VERSION 5.7 ;
  NOWIREEXTENSIONATPIN ON ;
  DIVIDERCHAR "/" ;
  BUSBITCHARS "[]" ;
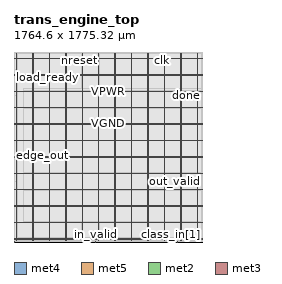
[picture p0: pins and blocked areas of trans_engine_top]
MACRO trans_engine_top
  CLASS BLOCK ;
  FOREIGN trans_engine_top ;
  ORIGIN 0.000 0.000 ;
  SIZE 1764.600 BY 1775.320 ;
  PIN VGND
    DIRECTION INOUT ;
    USE GROUND ;
    PORT
      LAYER met4 ;
        RECT 24.340 10.640 25.940 1762.800 ;
    END
    PORT
      LAYER met4 ;
        RECT 177.940 10.640 179.540 1762.800 ;
    END
    PORT
      LAYER met4 ;
        RECT 331.540 10.640 333.140 1762.800 ;
    END
    PORT
      LAYER met4 ;
        RECT 485.140 10.640 486.740 1762.800 ;
    END
    PORT
      LAYER met4 ;
        RECT 638.740 10.640 640.340 1762.800 ;
    END
    PORT
      LAYER met4 ;
        RECT 792.340 10.640 793.940 1762.800 ;
    END
    PORT
      LAYER met4 ;
        RECT 945.940 10.640 947.540 1762.800 ;
    END
    PORT
      LAYER met4 ;
        RECT 1099.540 10.640 1101.140 1762.800 ;
    END
    PORT
      LAYER met4 ;
        RECT 1253.140 10.640 1254.740 1762.800 ;
    END
    PORT
      LAYER met4 ;
        RECT 1406.740 10.640 1408.340 1762.800 ;
    END
    PORT
      LAYER met4 ;
        RECT 1560.340 10.640 1561.940 1762.800 ;
    END
    PORT
      LAYER met4 ;
        RECT 1713.940 10.640 1715.540 1762.800 ;
    END
    PORT
      LAYER met5 ;
        RECT 5.280 30.030 1759.280 31.630 ;
    END
    PORT
      LAYER met5 ;
        RECT 5.280 183.210 1759.280 184.810 ;
    END
    PORT
      LAYER met5 ;
        RECT 5.280 336.390 1759.280 337.990 ;
    END
    PORT
      LAYER met5 ;
        RECT 5.280 489.570 1759.280 491.170 ;
    END
    PORT
      LAYER met5 ;
        RECT 5.280 642.750 1759.280 644.350 ;
    END
    PORT
      LAYER met5 ;
        RECT 5.280 795.930 1759.280 797.530 ;
    END
    PORT
      LAYER met5 ;
        RECT 5.280 949.110 1759.280 950.710 ;
    END
    PORT
      LAYER met5 ;
        RECT 5.280 1102.290 1759.280 1103.890 ;
    END
    PORT
      LAYER met5 ;
        RECT 5.280 1255.470 1759.280 1257.070 ;
    END
    PORT
      LAYER met5 ;
        RECT 5.280 1408.650 1759.280 1410.250 ;
    END
    PORT
      LAYER met5 ;
        RECT 5.280 1561.830 1759.280 1563.430 ;
    END
    PORT
      LAYER met5 ;
        RECT 5.280 1715.010 1759.280 1716.610 ;
    END
  END VGND
  PIN VPWR
    DIRECTION INOUT ;
    USE POWER ;
    PORT
      LAYER met4 ;
        RECT 21.040 10.640 22.640 1762.800 ;
    END
    PORT
      LAYER met4 ;
        RECT 174.640 10.640 176.240 1762.800 ;
    END
    PORT
      LAYER met4 ;
        RECT 328.240 10.640 329.840 1762.800 ;
    END
    PORT
      LAYER met4 ;
        RECT 481.840 10.640 483.440 1762.800 ;
    END
    PORT
      LAYER met4 ;
        RECT 635.440 10.640 637.040 1762.800 ;
    END
    PORT
      LAYER met4 ;
        RECT 789.040 10.640 790.640 1762.800 ;
    END
    PORT
      LAYER met4 ;
        RECT 942.640 10.640 944.240 1762.800 ;
    END
    PORT
      LAYER met4 ;
        RECT 1096.240 10.640 1097.840 1762.800 ;
    END
    PORT
      LAYER met4 ;
        RECT 1249.840 10.640 1251.440 1762.800 ;
    END
    PORT
      LAYER met4 ;
        RECT 1403.440 10.640 1405.040 1762.800 ;
    END
    PORT
      LAYER met4 ;
        RECT 1557.040 10.640 1558.640 1762.800 ;
    END
    PORT
      LAYER met4 ;
        RECT 1710.640 10.640 1712.240 1762.800 ;
    END
    PORT
      LAYER met5 ;
        RECT 5.280 26.730 1759.280 28.330 ;
    END
    PORT
      LAYER met5 ;
        RECT 5.280 179.910 1759.280 181.510 ;
    END
    PORT
      LAYER met5 ;
        RECT 5.280 333.090 1759.280 334.690 ;
    END
    PORT
      LAYER met5 ;
        RECT 5.280 486.270 1759.280 487.870 ;
    END
    PORT
      LAYER met5 ;
        RECT 5.280 639.450 1759.280 641.050 ;
    END
    PORT
      LAYER met5 ;
        RECT 5.280 792.630 1759.280 794.230 ;
    END
    PORT
      LAYER met5 ;
        RECT 5.280 945.810 1759.280 947.410 ;
    END
    PORT
      LAYER met5 ;
        RECT 5.280 1098.990 1759.280 1100.590 ;
    END
    PORT
      LAYER met5 ;
        RECT 5.280 1252.170 1759.280 1253.770 ;
    END
    PORT
      LAYER met5 ;
        RECT 5.280 1405.350 1759.280 1406.950 ;
    END
    PORT
      LAYER met5 ;
        RECT 5.280 1558.530 1759.280 1560.130 ;
    END
    PORT
      LAYER met5 ;
        RECT 5.280 1711.710 1759.280 1713.310 ;
    END
  END VPWR
  PIN class_in[0]
    DIRECTION INPUT ;
    USE SIGNAL ;
    ANTENNAGATEAREA 0.426000 ;
    PORT
      LAYER met2 ;
        RECT 0.090 0.000 0.370 4.000 ;
    END
  END class_in[0]
  PIN class_in[1]
    DIRECTION INPUT ;
    USE SIGNAL ;
    ANTENNAGATEAREA 0.852000 ;
    PORT
      LAYER met2 ;
        RECT 1529.590 0.000 1529.870 4.000 ;
    END
  END class_in[1]
  PIN clk
    DIRECTION INPUT ;
    USE SIGNAL ;
    ANTENNAGATEAREA 0.852000 ;
    PORT
      LAYER met2 ;
        RECT 1381.470 1771.320 1381.750 1775.320 ;
    END
  END clk
  PIN done
    DIRECTION OUTPUT TRISTATE ;
    USE SIGNAL ;
    ANTENNADIFFAREA 0.445500 ;
    PORT
      LAYER met3 ;
        RECT 1760.600 1370.240 1764.600 1370.840 ;
    END
  END done
  PIN edge_out
    DIRECTION OUTPUT TRISTATE ;
    USE SIGNAL ;
    ANTENNADIFFAREA 0.795200 ;
    PORT
      LAYER met3 ;
        RECT 0.000 805.840 4.000 806.440 ;
    END
  END edge_out
  PIN in_valid
    DIRECTION INPUT ;
    USE SIGNAL ;
    ANTENNAGATEAREA 0.213000 ;
    PORT
      LAYER met2 ;
        RECT 763.230 0.000 763.510 4.000 ;
    END
  END in_valid
  PIN load_ready
    DIRECTION OUTPUT TRISTATE ;
    USE SIGNAL ;
    ANTENNADIFFAREA 0.795200 ;
    PORT
      LAYER met3 ;
        RECT 0.000 1615.040 4.000 1615.640 ;
    END
  END load_ready
  PIN nreset
    DIRECTION INPUT ;
    USE SIGNAL ;
    ANTENNAGATEAREA 0.126000 ;
    PORT
      LAYER met2 ;
        RECT 615.110 1771.320 615.390 1775.320 ;
    END
  END nreset
  PIN out_valid
    DIRECTION OUTPUT TRISTATE ;
    USE SIGNAL ;
    ANTENNADIFFAREA 0.445500 ;
    PORT
      LAYER met3 ;
        RECT 1760.600 561.040 1764.600 561.640 ;
    END
  END out_valid
  OBS
      LAYER li1 ;
        RECT 5.520 10.795 1759.040 1762.645 ;
      LAYER met1 ;
        RECT 0.070 10.640 1764.490 1762.800 ;
      LAYER met2 ;
        RECT 0.100 1771.040 614.830 1771.810 ;
        RECT 615.670 1771.040 1381.190 1771.810 ;
        RECT 1382.030 1771.040 1764.460 1771.810 ;
        RECT 0.100 4.280 1764.460 1771.040 ;
        RECT 0.650 3.670 762.950 4.280 ;
        RECT 763.790 3.670 1529.310 4.280 ;
        RECT 1530.150 3.670 1764.460 4.280 ;
      LAYER met3 ;
        RECT 4.000 1616.040 1763.115 1762.725 ;
        RECT 4.400 1614.640 1763.115 1616.040 ;
        RECT 4.000 1371.240 1763.115 1614.640 ;
        RECT 4.000 1369.840 1760.200 1371.240 ;
        RECT 4.000 806.840 1763.115 1369.840 ;
        RECT 4.400 805.440 1763.115 806.840 ;
        RECT 4.000 562.040 1763.115 805.440 ;
        RECT 4.000 560.640 1760.200 562.040 ;
        RECT 4.000 10.715 1763.115 560.640 ;
      LAYER met4 ;
        RECT 30.655 40.975 174.240 1761.025 ;
        RECT 176.640 40.975 177.540 1761.025 ;
        RECT 179.940 40.975 327.840 1761.025 ;
        RECT 330.240 40.975 331.140 1761.025 ;
        RECT 333.540 40.975 481.440 1761.025 ;
        RECT 483.840 40.975 484.740 1761.025 ;
        RECT 487.140 40.975 635.040 1761.025 ;
        RECT 637.440 40.975 638.340 1761.025 ;
        RECT 640.740 40.975 788.640 1761.025 ;
        RECT 791.040 40.975 791.940 1761.025 ;
        RECT 794.340 40.975 942.240 1761.025 ;
        RECT 944.640 40.975 945.540 1761.025 ;
        RECT 947.940 40.975 1095.840 1761.025 ;
        RECT 1098.240 40.975 1099.140 1761.025 ;
        RECT 1101.540 40.975 1249.440 1761.025 ;
        RECT 1251.840 40.975 1252.740 1761.025 ;
        RECT 1255.140 40.975 1403.040 1761.025 ;
        RECT 1405.440 40.975 1406.340 1761.025 ;
        RECT 1408.740 40.975 1556.640 1761.025 ;
        RECT 1559.040 40.975 1559.940 1761.025 ;
        RECT 1562.340 40.975 1710.240 1761.025 ;
        RECT 1712.640 40.975 1713.540 1761.025 ;
        RECT 1715.940 40.975 1752.730 1761.025 ;
      LAYER met5 ;
        RECT 87.980 1411.850 1752.940 1430.500 ;
        RECT 87.980 1258.670 1752.940 1403.750 ;
        RECT 87.980 1105.490 1752.940 1250.570 ;
        RECT 87.980 952.310 1752.940 1097.390 ;
        RECT 87.980 799.130 1752.940 944.210 ;
        RECT 87.980 645.950 1752.940 791.030 ;
        RECT 87.980 492.770 1752.940 637.850 ;
        RECT 87.980 339.590 1752.940 484.670 ;
        RECT 87.980 194.700 1752.940 331.490 ;
  END
END trans_engine_top
END LIBRARY

